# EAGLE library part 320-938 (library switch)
TOGGLE SWITCH distributor RS Components

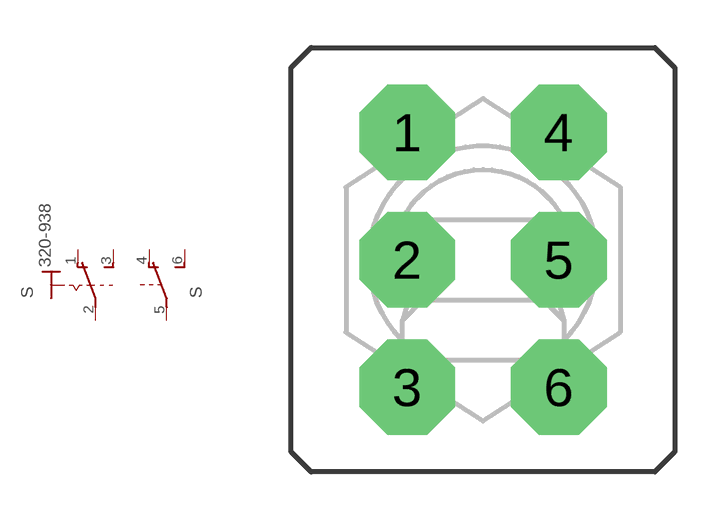
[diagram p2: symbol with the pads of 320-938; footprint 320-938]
Designator prefix S; gates B=U2 1=KS-U-

## 320-938  [320-938]
1  1:O  pas
2  1:P  pas
3  1:S  pas
4  B:O  pas
5  B:P  pas
6  B:S  pas

## Footprint 320-938 (pad centres in mm)
TOGGLE SWITCH distributor RS Components
drill 2.007 octagon: 1 -2.388,4.013; 2 -2.388,0; 3 -2.388,-4.013; 4 2.388,4.013; 5 2.388,0; 6 2.388,-4.013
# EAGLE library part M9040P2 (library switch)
TOGGLE SWITCH Marquardt

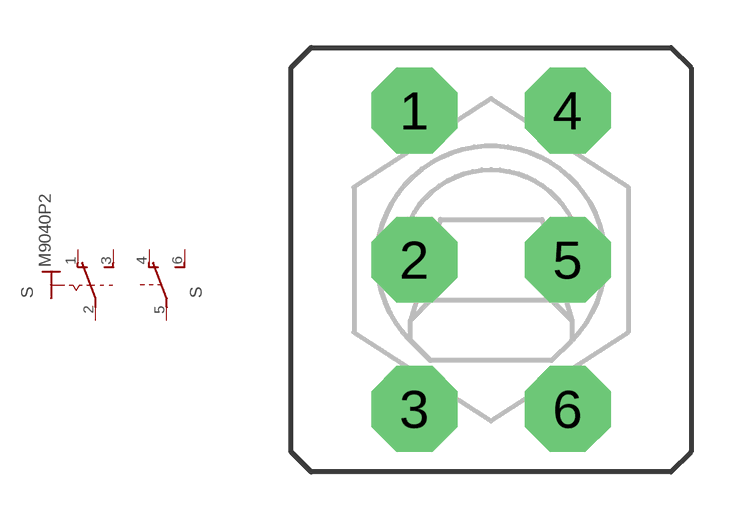
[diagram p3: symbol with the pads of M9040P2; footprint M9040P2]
Designator prefix S; gates 2=U2 1=KS-U-

## M9040P2  [M9040P2]
1  1:O  pas
2  1:P  pas
3  1:S  pas
4  2:O  pas
5  2:P  pas
6  2:S  pas

## Footprint M9040P2 (pad centres in mm)
TOGGLE SWITCH Marquardt
drill 1.803 octagon: 1 -2.413,4.699; 2 -2.413,0; 3 -2.413,-4.699; 4 2.413,4.699; 5 2.413,0; 6 2.413,-4.699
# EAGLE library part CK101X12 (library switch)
ROTARY SWITCH C&K

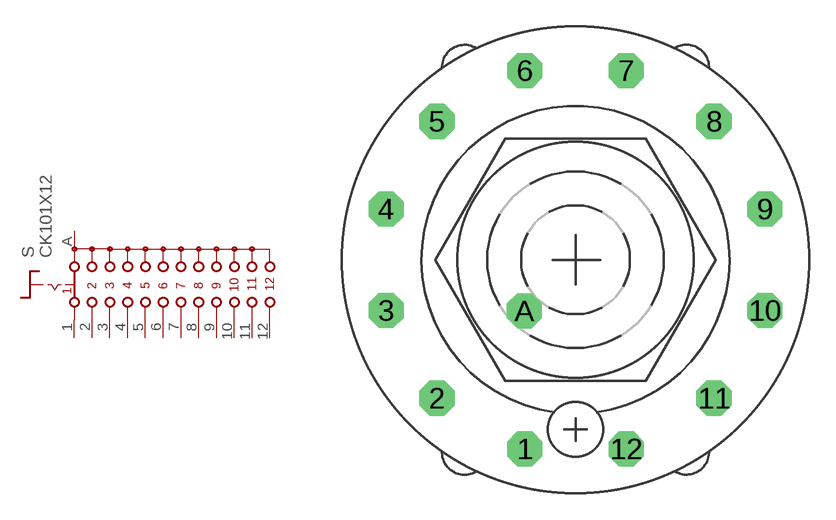
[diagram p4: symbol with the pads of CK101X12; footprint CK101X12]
Designator prefix S

## CK101X12  [CK101X12]
1  1  pas
2  2  pas
3  3  pas
4  4  pas
5  5  pas
6  6  pas
7  7  pas
8  8  pas
9  9  pas
10  10  pas
11  11  pas
12  12  pas
A  A  pas

## Footprint CK101X12 (pad centres in mm)
ROTARY SWITCH C&K
drill 1.321 octagon: 1 -2.845,-10.617; 2 -7.772,-7.772; 3 -10.617,-2.845; 4 -10.617,2.845; 5 -7.772,7.772; 6 -2.845,10.617; 7 2.845,10.617; 8 7.772,7.772; 9 10.617,2.845; 10 10.617,-2.845; 11 7.772,-7.772; 12 2.845,-10.617; A -2.87,-2.87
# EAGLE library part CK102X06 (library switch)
ROTARY SWITCH C&K

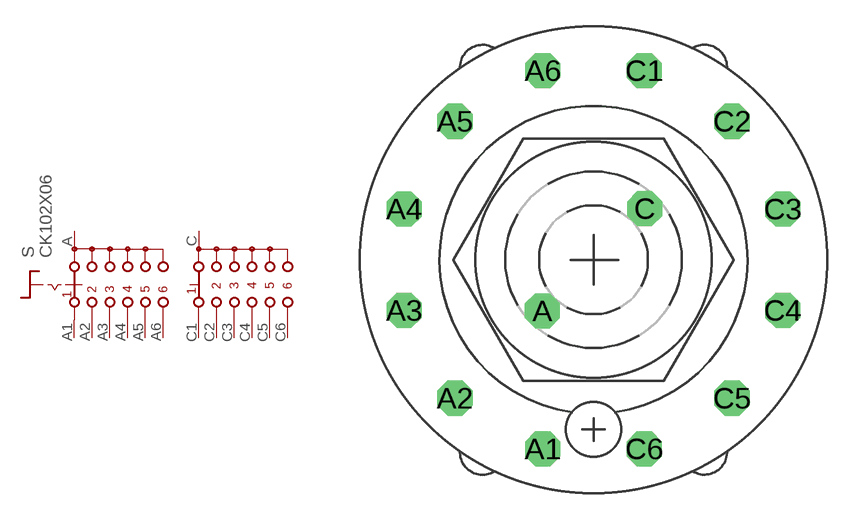
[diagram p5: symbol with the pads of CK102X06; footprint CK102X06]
Designator prefix S

## CK102X06  [CK102X06]
A  A  pas
A1  A1  pas
A2  A2  pas
A3  A3  pas
A4  A4  pas
A5  A5  pas
A6  A6  pas
C  C  pas
C1  C1  pas
C2  C2  pas
C3  C3  pas
C4  C4  pas
C5  C5  pas
C6  C6  pas

## Footprint CK102X06 (pad centres in mm)
ROTARY SWITCH C&K
drill 1.321 octagon: A -2.87,-2.87; A1 -2.845,-10.617; A2 -7.772,-7.772; A3 -10.617,-2.845; A4 -10.617,2.845; A5 -7.772,7.772; A6 -2.845,10.617; C 2.87,2.87; C1 2.845,10.617; C2 7.772,7.772; C3 10.617,2.845; C4 10.617,-2.845; C5 7.772,-7.772; C6 2.845,-10.617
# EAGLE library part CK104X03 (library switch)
ROTARY SWITCH C&K

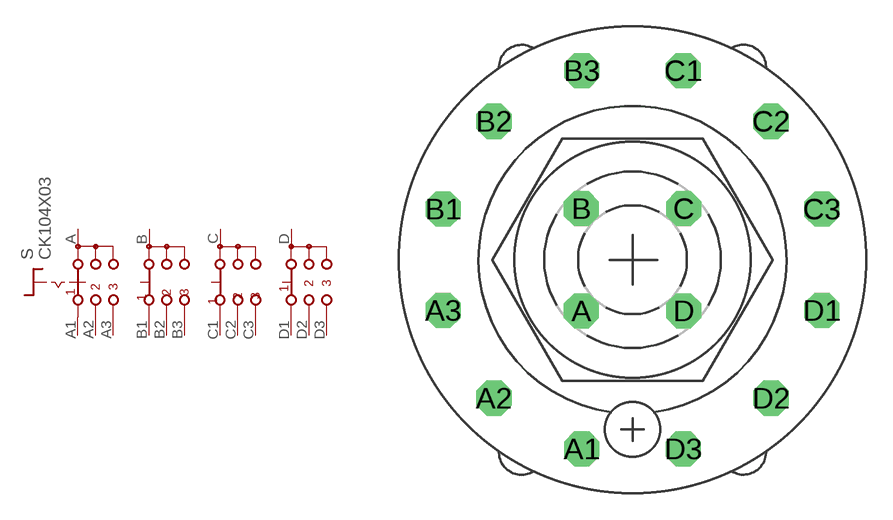
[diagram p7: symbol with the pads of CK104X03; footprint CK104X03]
Designator prefix S

## CK104X03  [CK104X03]
A  A  pas
A1  A1  pas
A2  A2  pas
A3  A3  pas
B  B  pas
B1  B1  pas
B2  B2  pas
B3  B3  pas
C  C  pas
C1  C1  pas
C2  C2  pas
C3  C3  pas
D  D  pas
D1  D1  pas
D2  D2  pas
D3  D3  pas

## Footprint CK104X03 (pad centres in mm)
ROTARY SWITCH C&K
drill 1.321 octagon: A -2.87,-2.87; A1 -2.845,-10.617; A2 -7.772,-7.772; A3 -10.617,-2.845; B -2.87,2.87; B1 -10.617,2.845; B2 -7.772,7.772; B3 -2.845,10.617; C 2.87,2.87; C1 2.845,10.617; C2 7.772,7.772; C3 10.617,2.845; D 2.87,-2.87; D1 10.617,-2.845; D2 7.772,-7.772; D3 2.845,-10.617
